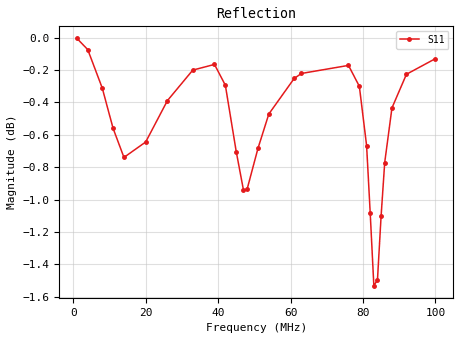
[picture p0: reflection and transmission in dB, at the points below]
# MHz S RI R 50.0
! SimSmith 18.4f
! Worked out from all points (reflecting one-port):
!   100 points, 1 MHz to 100 MHz, reference 50 ohm
!   lowest |S11| = -1.5 dB at 83 MHz (marker M1), VSWR 11.37, Z = 5.57 - j25.7 ohm
!   phase of S11 starts at -9 deg and turns -1028 deg over the sweep
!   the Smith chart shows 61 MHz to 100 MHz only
!   S11 on the Smith chart (normalised r, x): 61 MHz: 0.05, +1.62; 79 MHz: 4, -14; 83 MHz: 0.11, -0.51; 84 MHz: 0.09, -0.01; 86 MHz: 0.06, +0.65; 100 MHz: 0.06, +2.53
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1  0.9866 -0.1598
4  0.783 -0.6083
8  0.1339 -0.9555
11  -0.4869 -0.8012
14  -0.879 -0.266
20  -0.545 0.7517
26  0.1624 0.9423
33  0.7349 0.644
39  0.981 0.0153
42  0.7972 -0.5468
45  -0.1076 -0.9159
47  -0.7918 -0.4222
48  -0.8971 -0.0348
51  -0.5577 0.737
54  -0.1192 0.9396
61  0.438 0.867
63  0.5318 0.817
76  0.9429 0.2687
79  0.9575 -0.1275
81  0.677 -0.632
82  0.2082 -0.8578
83  -0.4833 -0.685
84  -0.8416 -0.0155
85  -0.6761 0.5644
86  -0.3704 0.8367
88  0.0757 0.9482
92  0.461 0.8583
100  0.7187 0.6738
